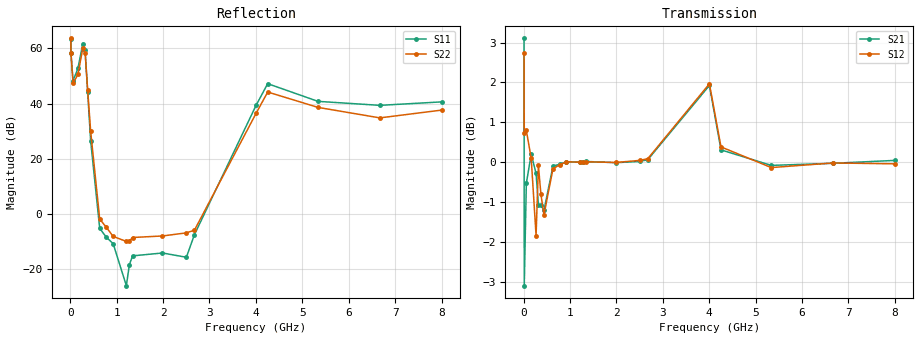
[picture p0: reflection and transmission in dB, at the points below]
!Agilent Technologies,N5230A,US43500312,A.07.50.67
!Agilent N5230A: A.07.50.67
!Date: Tuesday, June 09, 2015 15:34:54
!Correction: S11(Full 2 Port(1,2))
!S21(Full 2 Port(1,2))
!S12(Full 2 Port(1,2))
!S22(Full 2 Port(1,2))
!S2P File: Measurements: S11, S21, S12, S22:
# Hz S  MA  R 50
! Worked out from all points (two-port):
!   1601 points, 10 MHz to 8 GHz, reference 50 ohm
!   highest |S21| = 3.11 dB at 10 MHz (marker M1); lowest = -3.1 dB at 14.99 MHz (marker M2)
!   |S21| within 3 dB of the highest: 227.8 MHz to 259.9 MHz (32.13 MHz wide, 13.2 % of centre); 3.087 GHz to 4.279 GHz (1.192 GHz wide, 32.4 % of centre) (the widest 2 of 22)
!   lowest |S11| = -26.1 dB at 1.208 GHz (marker M3), VSWR 1.10, Z = 53.9 + j3.41 ohm
!   |S11| at or under -10 dB: 793.3 MHz to 942.5 MHz (149.2 MHz wide, 17.2 % of centre); 1.047 GHz to 2.09 GHz (1.043 GHz wide, 66.5 % of centre); 2.384 GHz to 2.63 GHz (246.3 MHz wide, 9.82 % of centre) (the widest 3 of 4)
!   |S22| runs from -13.9 to 63.6 dB; largest |S21 - S12| = 0.46
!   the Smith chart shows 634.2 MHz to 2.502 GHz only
!   S11 on the Smith chart (normalised r, x): 634.2 MHz: 0.40, +0.58; 779 MHz: 0.47, +0.15; 923.9 MHz: 0.94, -0.58; 1.273 GHz: 0.92, +0.21; 1.988 GHz: 0.68, +0.09; 2.502 GHz: 0.74, -0.11
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1e7  1498 171.2  1.43 -27.3  1.372 -46.0  1520 -19.4
1.499375e7  814.1 226.2  0.6997 19.4  1.089 23.4  827.4 32.4
5.99375e7  257.6 325.9  0.9408 -1.9  1.096 -9.4  232.3 92.3
1.648062e8  433.6 401.2  1.023 5.2  1.011 9.6  336.3 123.4
2.69675e8  1222 383.1  0.9679 1.8  0.8089 -16.1  997.7 100.7
3.196125e8  929.9 421.4  0.8846 4.6  0.9905 -6.0  842 146.2
3.745438e8  162.5 434.1  0.8825 2.9  0.9109 2.0  178.3 176.2
4.394625e8  20.95 415.2  0.8697 4.0  0.8585 4.5  31.32 196.3
6.342188e8  0.5452 473.7  0.989 8.3  0.9812 8.4  0.803 373.2
7.790375e8  0.3738 517.8  0.9937 6.4  0.9922 6.1  0.5664 453.9
9.238562e8  0.288 640.6  1.001 6.1  1.001 6.1  0.389 574.0
1.2085e9  0.04969 759.4  1 6.5  0.9998 6.6  0.3153 691.2
1.273419e9  0.1191 825.2  1.001 6.5  1.001 6.6  0.3218 732.4
1.343331e9  0.1727 840.3  1.002 6.5  1.001 6.5  0.3717 763.9
1.987525e9  0.1947 880.8  0.9984 6.1  0.999 6.1  0.3964 1033.1
2.501881e9  0.1629 927.0  1.002 6.8  1.005 6.8  0.451 1154.5
2.676662e9  0.4199 1020.1  1.007 6.9  1.01 6.9  0.5055 1230.5
4.005e9  93.08 1393.6  1.248 -0.6  1.254 -0.5  66.59 1521.1
4.254688e9  229.2 1342.2  1.036 -8.3  1.045 -7.2  161.6 1459.1
5.338331e9  109.5 1320.4  0.9906 0.6  0.9844 1.0  85.11 1400.2
6.671662e9  92.64 1358.0  0.9966 0.7  0.9976 0.9  54.92 1339.4
8e9  107.1 1386.4  1.005 0.9  0.9951 0.9  75.93 1307.6
